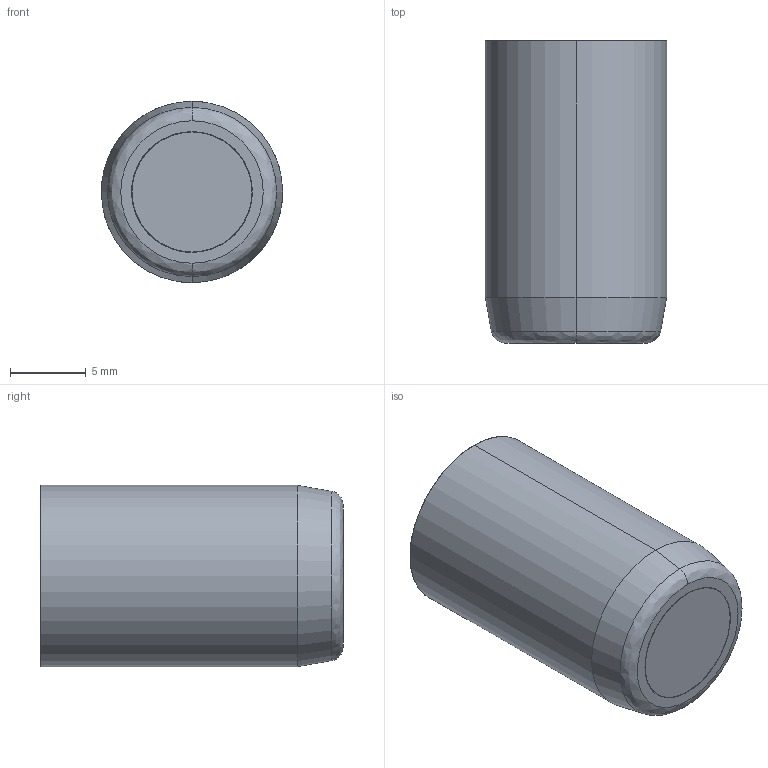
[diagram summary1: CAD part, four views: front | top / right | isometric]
IGES file: header records copied from the file, then geometry measured from it (millimetres).
Start section: START RECORD GO HERE.
Global section: file name: fa126700.igs; native system: DASSAULT SYSTEMES CATIA V5 R20 - www.3ds.com; preprocessor: CATIA Version 5 Release 20 ; author: Utente; organization: NB04-ASUS; date: 20201108.083629; units: millimetre
Bounding box: 12 x 20 x 12 mm (x, y, z)
Surface area: 2171.7 mm2 (no closed solid volume)
Topology: 0 solids, 0 shells, 183 faces, 813 edges, 810 vertices
Faces by surface type: revolution 72, bspline 68, plane 43
